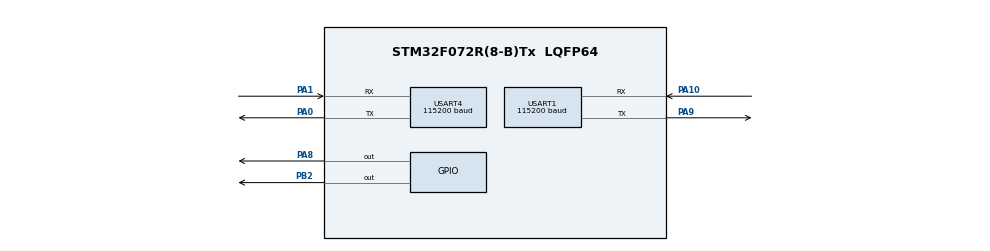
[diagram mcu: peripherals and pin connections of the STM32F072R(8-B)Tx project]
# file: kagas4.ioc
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Mcu.Family=STM32F0
Mcu.Name=STM32F072R(8-B)Tx
Mcu.Package=LQFP64
NVIC.USART1_IRQn=true\:0\:0\:false\:false\:true\:true
NVIC.USART3_4_IRQn=true\:0\:0\:false\:false\:true\:true
PA0.Mode=Asynchronous
PA0.Signal=USART4_TX
PA1.Mode=Asynchronous
PA1.Signal=USART4_RX
PA10.Mode=Asynchronous
PA10.Signal=USART1_RX
PA8.Signal=GPIO_Output
PA9.Mode=Asynchronous
PA9.Signal=USART1_TX
PB2.Signal=GPIO_Output
ProjectManager.HeapSize=0x200
ProjectManager.StackSize=0x400
ProjectManager.TargetToolchain=TrueSTUDIO
USART1.BaudRate=115200
USART1.VirtualMode-Asynchronous=VM_ASYNC
USART4.BaudRate=115200
USART4.VirtualMode-Asynchronous=VM_ASYNC
board=custom

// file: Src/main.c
/* USER CODE BEGIN Header */
/**
  ******************************************************************************
  * @file           : main.c
  * @brief          : Main program body
  ******************************************************************************
  ** This notice applies to any and all portions of this file
  * that are not between comment pairs USER CODE BEGIN and
  * USER CODE END. Other portions of this file, whether
  * inserted by the user or by software development tools
  * are owned by their respective copyright owners.
  *
  * COPYRIGHT(c) 2020 STMicroelectronics
  *
  * Redistribution and use in source and binary forms, with or without modification,
  * are permitted provided that the following conditions are met:
  *   1. Redistributions of source code must retain the above copyright notice,
  *      this list of conditions and the following disclaimer.
  *   2. Redistributions in binary form must reproduce the above copyright notice,
  *      this list of conditions and the following disclaimer in the documentation
  *      and/or other materials provided with the distribution.
  *   3. Neither the name of STMicroelectronics nor the names of its contributors
  *      may be used to endorse or promote products derived from this software
  *      without specific prior written permission.
  *
  * THIS SOFTWARE IS PROVIDED BY THE COPYRIGHT HOLDERS AND CONTRIBUTORS "AS IS"
  * AND ANY EXPRESS OR IMPLIED WARRANTIES, INCLUDING, BUT NOT LIMITED TO, THE
  * IMPLIED WARRANTIES OF MERCHANTABILITY AND FITNESS FOR A PARTICULAR PURPOSE ARE
  * DISCLAIMED. IN NO EVENT SHALL THE COPYRIGHT HOLDER OR CONTRIBUTORS BE LIABLE
  * FOR ANY DIRECT, INDIRECT, INCIDENTAL, SPECIAL, EXEMPLARY, OR CONSEQUENTIAL
  * DAMAGES (INCLUDING, BUT NOT LIMITED TO, PROCUREMENT OF SUBSTITUTE GOODS OR
  * SERVICES; LOSS OF USE, DATA, OR PROFITS; OR BUSINESS INTERRUPTION) HOWEVER
  * CAUSED AND ON ANY THEORY OF LIABILITY, WHETHER IN CONTRACT, STRICT LIABILITY,
  * OR TORT (INCLUDING NEGLIGENCE OR OTHERWISE) ARISING IN ANY WAY OUT OF THE USE
  * OF THIS SOFTWARE, EVEN IF ADVISED OF THE POSSIBILITY OF SUCH DAMAGE.
  *
  ******************************************************************************
  */
/* USER CODE END Header */

#include "main.h"
#include <stdio.h>
#include <string.h>
#include <stdbool.h>

UART_HandleTypeDef huart1;
UART_HandleTypeDef huart4;

void SystemClock_Config(void);
static void MX_GPIO_Init(void);
static void MX_USART1_UART_Init(void);
static void MX_USART4_UART_Init(void);

/* USER CODE BEGIN 0 */
extern uint8_t rxFlag;
extern uint8_t rxData[200];
extern uint8_t wakeUpFlag;
extern uint8_t setup1Flag;
extern uint8_t setup2Flag;
extern uint8_t readyGSM;
extern uint8_t readyReception;
extern uint8_t OK;

uint8_t atCommand[] = "AT\r\n";
uint8_t simReception[] = "AT+CSQ\r\n";
uint8_t simSetup1[] = "AT+CMGF=1\r\n";
uint8_t simSetup2[] = "AT+CSCS=\"GSM\"\r\n";
uint8_t message2Phone[] = "AT+CMGS=\"+905074471728\"\r\n >KAGAS test baslangic mesaji \x1A";
uint8_t beginMessage[] = "KAGAS test baslangic mesaji \x1A"; // 28
uint8_t testMessage[] = "KAGAS test mesaji \x1A"; // 19
uint8_t outputState = 0;
uint8_t isBegin = 1;

int getMsg = 1;
int firstMsg = 0;
/* USER CODE END 0 */

int main(void)
{

  /* MCU Configuration--------------------------------------------------------*/

  /* Reset of all peripherals, Initializes the Flash interface and the Systick. */
  HAL_Init();

  /* Configure the system clock */
  SystemClock_Config();

  /* Initialize all configured peripherals */
  MX_GPIO_Init();
  MX_USART1_UART_Init();
  MX_USART4_UART_Init();
  /* USER CODE BEGIN 2 */

  //__HAL_UART_ENABLE_IT(&huart4,UART_IT_RXNE);
  __HAL_UART_ENABLE_IT(&huart1,UART_IT_RXNE);
  /* USER CODE END 2 */
  /* Infinite loop */
  /* USER CODE BEGIN WHILE */;

  /****///wake up m66
  // This part required for wake up to m66 so here is we do that push down to PIN_8 //

  	HAL_GPIO_WritePin(GPIOA,GPIO_PIN_8,GPIO_PIN_SET);
  	HAL_GPIO_WritePin(GPIOB,GPIO_PIN_2,GPIO_PIN_SET);
    HAL_Delay(1500);
    HAL_GPIO_WritePin(GPIOA,GPIO_PIN_8,GPIO_PIN_RESET);
    HAL_GPIO_WritePin(GPIOB,GPIO_PIN_2,GPIO_PIN_RESET);
    HAL_Delay(3000);

  /*****/

/****/
    // in here we're send at command cause of this first at command reqiured to detect baundrate
	 HAL_UART_Transmit(&huart1,(uint8_t *)atCommand,strlen(atCommand),100);
	 HAL_Delay(2000);
/****/

/****/

// if you see one toggle in board led pin, gprs reception is not enough

/****/
  while (1)
  {
    /* USER CODE END WHILE */
	  //HAL_UART_Transmit(&huart4,"AT\r\n",4,100);
	  //HAL_GPIO_TogglePin(GPIOB,GPIO_PIN_2);

	  if(HAL_GPIO_ReadPin(GPIOB,GPIO_PIN_5) == 1){
		  HAL_GPIO_WritePin(GPIOB,GPIO_PIN_4,GPIO_PIN_SET);
		  outputState = 1;
	  }
	  else{
		  if(outputState){
			  HAL_GPIO_WritePin(GPIOB,GPIO_PIN_4,GPIO_PIN_RESET);
			  outputState = 0;
		  }
	  }

	  if(wakeUpFlag || (HAL_GPIO_ReadPin(GPIOA,GPIO_PIN_4) == 1 && firstMsg)){ // || HAL_GPIO_ReadPin(GPIOA,GPIO_PIN_4) == 1

		  if(getMsg == 1){
				HAL_GPIO_WritePin(GPIOB,GPIO_PIN_2,GPIO_PIN_SET);
				HAL_Delay(200);
				HAL_GPIO_WritePin(GPIOB,GPIO_PIN_2,GPIO_PIN_RESET);
				HAL_Delay(200);
				wakeUpFlag = 0;
				rxFlag = 0;
				getMsg = 0;
				HAL_Delay(100);
				HAL_UART_Transmit(&huart1,(uint8_t *)simReception,strlen(simReception),100);
		  }
	  }
	  if(readyReception){ // AT+CMGF=1\r\n
			HAL_UART_Transmit(&huart1, (uint8_t *)simSetup1,strlen(simSetup1),100);
			readyReception = 0;
			rxFlag = 0;
	  }
	  if(setup1Flag){ // AT+CSCS=\"GSM\"\r\n
			HAL_UART_Transmit(&huart1, (uint8_t *)simSetup2,strlen(simSetup2),100);
			setup1Flag = 0;
			rxFlag = 0;
	  }
	  if(setup2Flag){
	  		  HAL_UART_Transmit(&huart1, (uint8_t *)message2Phone,strlen(message2Phone),100);
	  		  setup2Flag = 0;
	  		  rxFlag = 0;
	  }
  }
}

void SystemClock_Config(void)
{
  RCC_OscInitTypeDef RCC_OscInitStruct = {0};
  RCC_ClkInitTypeDef RCC_ClkInitStruct = {0};
  RCC_PeriphCLKInitTypeDef PeriphClkInit = {0};

  /**Initializes the CPU, AHB and APB busses clocks
  */
  RCC_OscInitStruct.OscillatorType = RCC_OSCILLATORTYPE_HSI;
  RCC_OscInitStruct.HSIState = RCC_HSI_ON;
  RCC_OscInitStruct.HSICalibrationValue = RCC_HSICALIBRATION_DEFAULT;
  RCC_OscInitStruct.PLL.PLLState = RCC_PLL_NONE;
  if (HAL_RCC_OscConfig(&RCC_OscInitStruct) != HAL_OK)
  {
    Error_Handler();
  }
  /**Initializes the CPU, AHB and APB busses clocks
  */
  RCC_ClkInitStruct.ClockType = RCC_CLOCKTYPE_HCLK|RCC_CLOCKTYPE_SYSCLK
                              |RCC_CLOCKTYPE_PCLK1;
  RCC_ClkInitStruct.SYSCLKSource = RCC_SYSCLKSOURCE_HSI;
  RCC_ClkInitStruct.AHBCLKDivider = RCC_SYSCLK_DIV1;
  RCC_ClkInitStruct.APB1CLKDivider = RCC_HCLK_DIV1;

  if (HAL_RCC_ClockConfig(&RCC_ClkInitStruct, FLASH_LATENCY_0) != HAL_OK)
  {
    Error_Handler();
  }
  PeriphClkInit.PeriphClockSelection = RCC_PERIPHCLK_USART1;
  PeriphClkInit.Usart1ClockSelection = RCC_USART1CLKSOURCE_PCLK1;
  if (HAL_RCCEx_PeriphCLKConfig(&PeriphClkInit) != HAL_OK)
  {
    Error_Handler();
  }
}

static void MX_USART1_UART_Init(void)
{

  huart1.Instance = USART1;
  huart1.Init.BaudRate = 115200;
  huart1.Init.WordLength = UART_WORDLENGTH_8B;
  huart1.Init.StopBits = UART_STOPBITS_1;
  huart1.Init.Parity = UART_PARITY_NONE;
  huart1.Init.Mode = UART_MODE_TX_RX;
  huart1.Init.HwFlowCtl = UART_HWCONTROL_NONE;
  huart1.Init.OverSampling = UART_OVERSAMPLING_16;
  huart1.Init.OneBitSampling = UART_ONE_BIT_SAMPLE_DISABLE;
  huart1.AdvancedInit.AdvFeatureInit = UART_ADVFEATURE_NO_INIT;
  if (HAL_UART_Init(&huart1) != HAL_OK)
  {
    Error_Handler();
  }

}

static void MX_USART4_UART_Init(void)
{

  huart4.Instance = USART4;
  huart4.Init.BaudRate = 115200;
  huart4.Init.WordLength = UART_WORDLENGTH_8B;
  huart4.Init.StopBits = UART_STOPBITS_1;
  huart4.Init.Parity = UART_PARITY_NONE;
  huart4.Init.Mode = UART_MODE_TX_RX;
  huart4.Init.HwFlowCtl = UART_HWCONTROL_NONE;
  huart4.Init.OverSampling = UART_OVERSAMPLING_16;
  huart4.Init.OneBitSampling = UART_ONE_BIT_SAMPLE_DISABLE;
  huart4.AdvancedInit.AdvFeatureInit = UART_ADVFEATURE_NO_INIT;
  if (HAL_UART_Init(&huart4) != HAL_OK)
  {
    Error_Handler();
  }

}

static void MX_GPIO_Init(void)
{
  GPIO_InitTypeDef GPIO_InitStruct = {0};

  /* GPIO Ports Clock Enable */
  __HAL_RCC_GPIOA_CLK_ENABLE();
  __HAL_RCC_GPIOB_CLK_ENABLE();

  /*Configure GPIO pin Output Level */
  HAL_GPIO_WritePin(GPIOB, GPIO_PIN_2, GPIO_PIN_RESET);
  HAL_GPIO_WritePin(GPIOB, GPIO_PIN_4, GPIO_PIN_RESET);

  /*Configure GPIO pin Output Level */
  HAL_GPIO_WritePin(GPIOA, GPIO_PIN_8, GPIO_PIN_RESET);

  /*Configure GPIO pin : PB2 */
  GPIO_InitStruct.Pin = GPIO_PIN_2;
  GPIO_InitStruct.Mode = GPIO_MODE_OUTPUT_PP;
  GPIO_InitStruct.Pull = GPIO_NOPULL;
  GPIO_InitStruct.Speed = GPIO_SPEED_FREQ_LOW;
  HAL_GPIO_Init(GPIOB, &GPIO_InitStruct);

  /*Configure GPIO pin : PB4 */
  GPIO_InitStruct.Pin = GPIO_PIN_4;
  GPIO_InitStruct.Mode = GPIO_MODE_OUTPUT_PP;
  GPIO_InitStruct.Pull = GPIO_NOPULL;
  GPIO_InitStruct.Speed = GPIO_SPEED_FREQ_LOW;
  HAL_GPIO_Init(GPIOB, &GPIO_InitStruct);

  /*Configure GPIO pin : PA8 */
  GPIO_InitStruct.Pin = GPIO_PIN_8;
  GPIO_InitStruct.Mode = GPIO_MODE_OUTPUT_PP;
  GPIO_InitStruct.Pull = GPIO_NOPULL;
  GPIO_InitStruct.Speed = GPIO_SPEED_FREQ_LOW;
  HAL_GPIO_Init(GPIOA, &GPIO_InitStruct);

  /*Configure GPIO pin : PB4 */
    GPIO_InitStruct.Pin = GPIO_PIN_4;
    GPIO_InitStruct.Mode = GPIO_MODE_OUTPUT_PP;
    GPIO_InitStruct.Pull = GPIO_NOPULL;
    GPIO_InitStruct.Speed = GPIO_SPEED_FREQ_LOW;
    HAL_GPIO_Init(GPIOB, &GPIO_InitStruct);

    /*Configure GPIO pin : PB5 */
    GPIO_InitStruct.Pin = GPIO_PIN_5;
    GPIO_InitStruct.Mode = GPIO_MODE_INPUT;
    GPIO_InitStruct.Pull = GPIO_NOPULL;
    HAL_GPIO_Init(GPIOB, &GPIO_InitStruct);

    /*Configure GPIO pin : PA4 */
	GPIO_InitStruct.Pin = GPIO_PIN_4;
	GPIO_InitStruct.Mode = GPIO_MODE_INPUT;
	GPIO_InitStruct.Pull = GPIO_NOPULL;
	HAL_GPIO_Init(GPIOA, &GPIO_InitStruct);
}

/* USER CODE BEGIN 4 */
void HAL_UART_RxCpltCallback(UART_HandleTypeDef *huart)
{

}
void HAL_UART_TxCpltCallback(UART_HandleTypeDef *huart)
{

}
/* USER CODE END 4 */

void Error_Handler(void)
{
}

/************************ (C) COPYRIGHT STMicroelectronics *****END OF FILE****/
